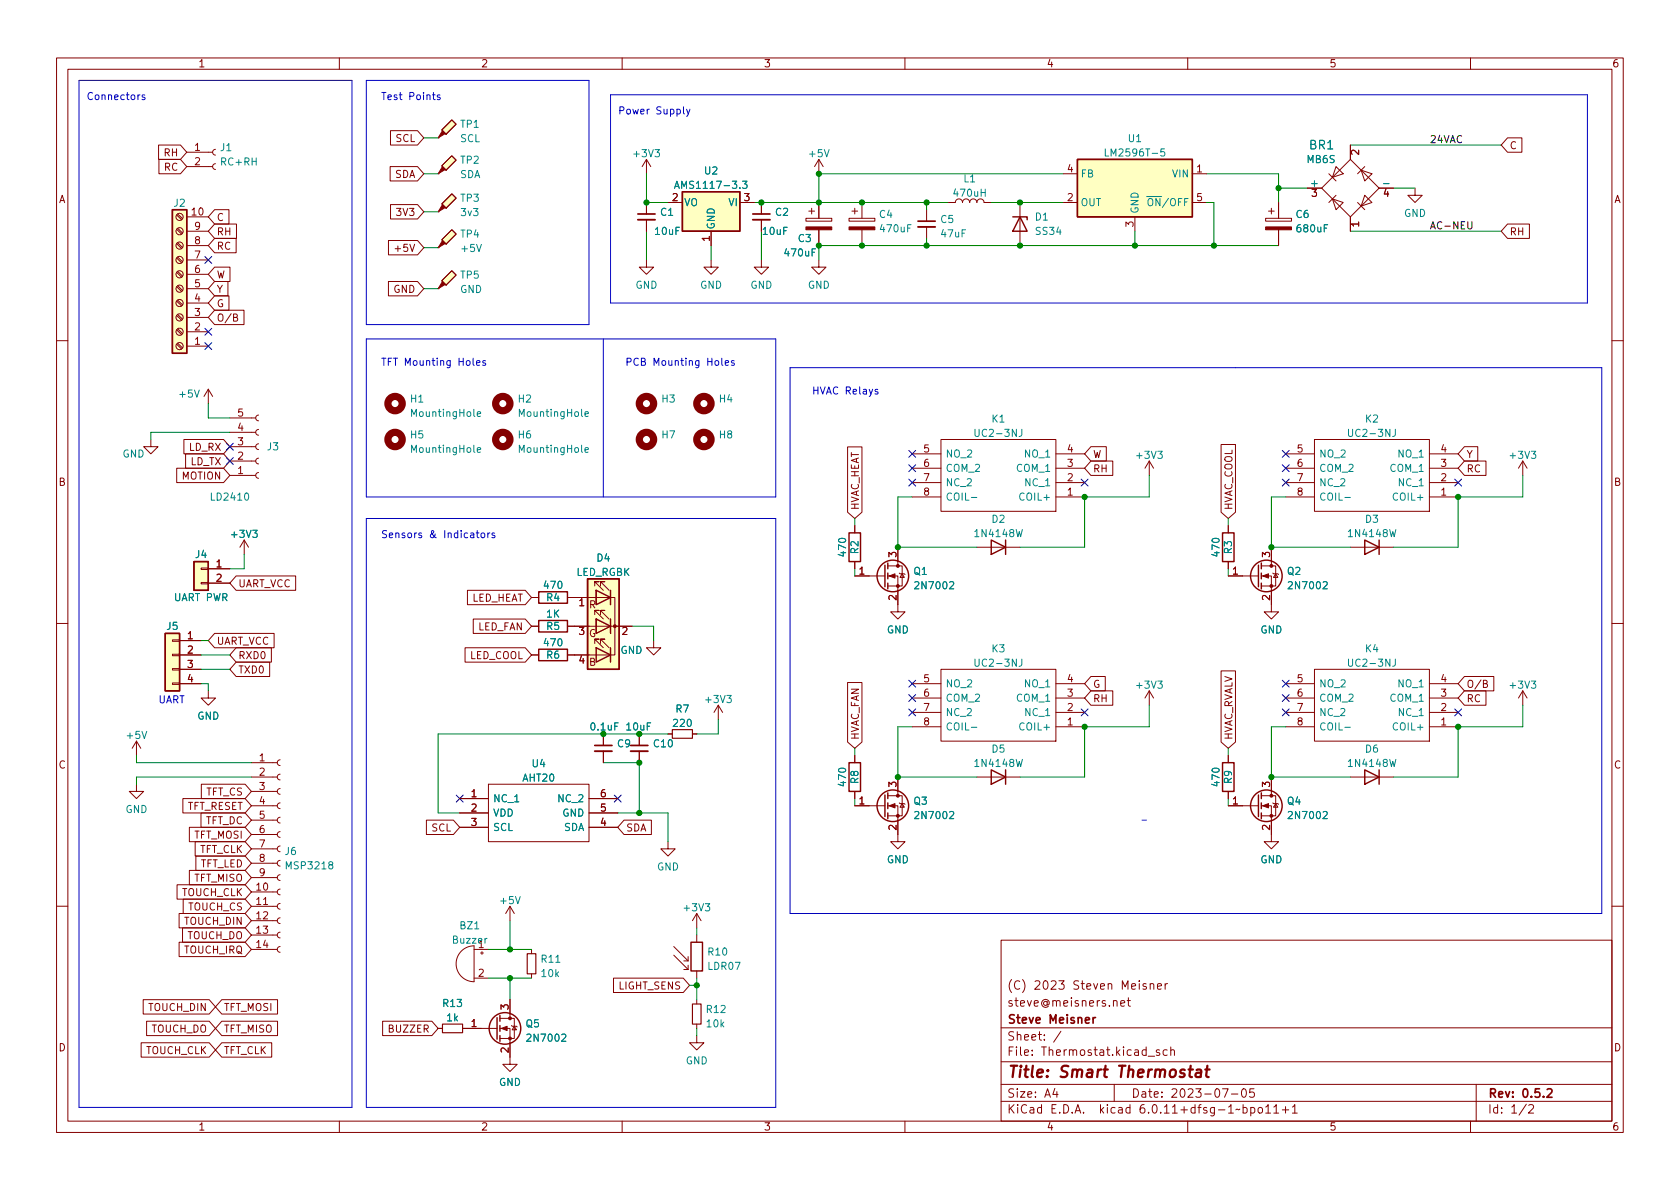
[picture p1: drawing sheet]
<svg xmlns="http://www.w3.org/2000/svg" width="297mm" height="210mm" viewBox="0 0 297 210" stroke-linecap="round" stroke-linejoin="round" font-family="sans-serif">
<defs><g id="words">
<g font-size="2.8" fill="#840000">
<text x="178" y="191.2">Title:</text>
<text x="187.3" y="191.2">Smart</text>
<text x="197.9" y="191.2">Thermostat</text>
</g>
<text font-size="2.1" fill="#008484" x="231.4" y="26.9">BR1</text>
<g font-size="2.1" fill="#840000">
<text x="178" y="178.5">steve@meisners.net</text>
<text x="178" y="175.5">(C)</text>
<text x="182.8" y="175.5">2023</text>
<text x="189.8" y="175.5">Steven</text>
<text x="198.5" y="175.5">Meisner</text>
<text x="178" y="184.5">Sheet:</text>
<text x="178" y="181.5">Steve</text>
<text x="185.4" y="181.5">Meisner</text>
<text x="178" y="187.2">File:</text>
<text x="184.4" y="187.2">Thermostat.kicad_sch</text>
<text x="178" y="197.4">KiCad</text>
<text x="178" y="194.6">Size:</text>
<text x="184.7" y="194.6">A4</text>
<text x="185.7" y="197.4">E.D.A.</text>
<text x="194.6" y="197.4">kicad</text>
<text x="200" y="194.6">Date:</text>
<text x="201.8" y="197.4">6.0.11+dfsg-1~bpo11+1</text>
<text x="207" y="194.6">2023-07-05</text>
<text x="263" y="194.6">Rev:</text>
<text x="263" y="197.4">Id:</text>
<text x="267.1" y="197.4">1/2</text>
<text x="269.1" y="194.6">0.5.2</text>
</g>
<g font-size="1.8" fill="#0000c2">
<text x="15.2" y="17.7">Connectors</text>
<text x="67.3" y="17.7">Test</text>
<text x="72.2" y="17.7">Points</text>
<text x="109.2" y="20.2">Power</text>
<text x="116" y="20.2">Supply</text>
<text x="67.3" y="64.7">TFT Mounting</text>
<text x="81.1" y="64.7">Holes</text>
<text x="110.5" y="64.7">PCB</text>
<text x="115.4" y="64.7">Mounting</text>
<text x="125.1" y="64.7">Holes</text>
<text x="143.5" y="69.7">HVAC Relays</text>
<text x="67.3" y="95.1">Sensors</text>
<text x="75.9" y="95.1">&amp;</text>
<text x="78.6" y="95.1">Indicators</text>
<text x="27.9" y="124.4">UART</text>
</g>
<g font-size="1.8" fill="#840000">
<text x="35" y="12.3">1</text>
<text x="85" y="12.3">2</text>
<text x="135" y="12.3">3</text>
<text x="185" y="12.3">4</text>
<text x="235" y="12.3">5</text>
<text x="285" y="12.3">6</text>
<text x="28.8" y="28">RH</text>
<text x="34.2" y="26.7">1</text>
<text x="34.2" y="29.2">2</text>
<text x="69.8" y="25.5">SCL</text>
<text x="266.9" y="26.8">C</text>
<text x="28.9" y="30.6">RC</text>
<text x="69.8" y="31.8">SDA</text>
<text x="118.7" y="35.6">2</text>
<text x="131.4" y="35.6">3</text>
<text x="188.5" y="35.6">2</text>
<text x="188.5" y="30.5">4</text>
<text x="211.4" y="30.5">1</text>
<text x="211.4" y="35.6">5</text>
<text x="244.4" y="35.6">4</text>
<text x="10.4" y="36.3">A</text>
<text x="33.6" y="38.1">10</text>
<text x="34.2" y="40.6">9</text>
<text x="38.3" y="39.5">C</text>
<text x="69.8" y="38.6">3V3</text>
<text x="200.4" y="40.3" transform="rotate(-90 200.4 40.3)">3</text>
<text x="241.1" y="40.3" transform="rotate(-90 241.1 40.3)">1</text>
<text x="285.4" y="36.3">A</text>
<text x="34.2" y="45.7">7</text>
<text x="34.2" y="43.2">8</text>
<text x="38.3" y="42">RH</text>
<text x="38.3" y="44.5">RC</text>
<text x="69.5" y="44.9">+5V</text>
<text x="125.5" y="42.8" transform="rotate(-90 125.5 42.8)">1</text>
<text x="266.9" y="42">RH</text>
<text x="34.2" y="53.3">4</text>
<text x="34.2" y="50.8">5</text>
<text x="34.2" y="48.3">6</text>
<text x="38.3" y="49.6">W</text>
<text x="38.3" y="52.2">Y</text>
<text x="69.5" y="52.2">GND</text>
<text x="34.2" y="58.4">2</text>
<text x="34.2" y="55.9">3</text>
<text x="38.3" y="54.7">G</text>
<text x="38.3" y="57.2">O/B</text>
<text x="34.2" y="61">1</text>
<text x="41.9" y="76.2">4</text>
<text x="41.9" y="73.7">5</text>
<text x="33.3" y="80.1">LD_RX</text>
<text x="33.6" y="82.6">LD_TX</text>
<text x="41.9" y="83.8">1</text>
<text x="41.9" y="81.3">2</text>
<text x="41.9" y="78.7">3</text>
<text x="163.1" y="80">5</text>
<text x="163.1" y="82.5">6</text>
<text x="188.5" y="82.5">3</text>
<text x="188.5" y="80">4</text>
<text x="193.2" y="81.4">W</text>
<text x="193.2" y="83.9">RH</text>
<text x="229.2" y="80">5</text>
<text x="229.2" y="82.5">6</text>
<text x="254.6" y="82.5">3</text>
<text x="254.6" y="80">4</text>
<text x="259.2" y="81.4">Y</text>
<text x="259.2" y="83.9">RC</text>
<text x="10.3" y="86.3">B</text>
<text x="32" y="85.2">MOTION</text>
<text x="163.1" y="85.1">7</text>
<text x="163.1" y="87.6">8</text>
<text x="188.5" y="87.6">1</text>
<text x="188.5" y="85.1">2</text>
<text x="229.2" y="85.1">7</text>
<text x="229.2" y="87.6">8</text>
<text x="254.6" y="87.6">1</text>
<text x="254.6" y="85.1">2</text>
<text x="285.3" y="86.3">B</text>
<text x="152.2" y="90.3" transform="rotate(-90 152.2 90.3)">HVAC_HEAT</text>
<text x="218.3" y="90.3" transform="rotate(-90 218.3 90.3)">HVAC_COOL</text>
<text x="38.1" y="100.3">1</text>
<text x="151.7" y="101.6">1</text>
<text x="158.5" y="98.7" transform="rotate(-90 158.5 98.7)">3</text>
<text x="217.8" y="101.6">1</text>
<text x="224.5" y="98.7" transform="rotate(-90 224.5 98.7)">3</text>
<text x="38.1" y="102.9">2</text>
<text x="42.1" y="104.2">UART_VCC</text>
<text x="83.4" y="106.8">LED_HEAT</text>
<text x="102.2" y="108">1</text>
<text x="104.1" y="108">R</text>
<text x="158.5" y="106.3" transform="rotate(-90 158.5 106.3)">2</text>
<text x="224.5" y="106.3" transform="rotate(-90 224.5 106.3)">2</text>
<text x="33" y="113">1</text>
<text x="84.5" y="111.9">LED_FAN</text>
<text x="104.1" y="113">G</text>
<text x="33" y="115.6">2</text>
<text x="33" y="118.1">3</text>
<text x="38.3" y="114.4">UART_VCC</text>
<text x="42.1" y="119.5">TXD0</text>
<text x="42.1" y="116.9">RXD0</text>
<text x="83" y="116.9">LED_COOL</text>
<text x="102.2" y="118.1">4</text>
<text x="104.1" y="118.1">B</text>
<text x="33" y="120.6">4</text>
<text x="163.1" y="120.6">5</text>
<text x="163.1" y="123.2">6</text>
<text x="163.1" y="125.7">7</text>
<text x="188.5" y="125.7">2</text>
<text x="188.5" y="123.2">3</text>
<text x="188.5" y="120.6">4</text>
<text x="193.2" y="124.6">RH</text>
<text x="193.2" y="122">G</text>
<text x="229.2" y="120.6">5</text>
<text x="229.2" y="123.2">6</text>
<text x="229.2" y="125.7">7</text>
<text x="254.6" y="125.7">2</text>
<text x="254.6" y="123.2">3</text>
<text x="254.6" y="120.6">4</text>
<text x="259.2" y="122">O/B</text>
<text x="259.2" y="124.6">RC</text>
<text x="152.2" y="130.9" transform="rotate(-90 152.2 130.9)">HVAC_FAN</text>
<text x="163.1" y="128.3">8</text>
<text x="188.5" y="128.3">1</text>
<text x="218.3" y="130.9" transform="rotate(-90 218.3 130.9)">HVAC_RVALV</text>
<text x="229.2" y="128.3">8</text>
<text x="254.6" y="128.3">1</text>
<text x="10.3" y="136.3">C</text>
<text x="45.7" y="134.6">1</text>
<text x="45.7" y="137.2">2</text>
<text x="285.3" y="136.3">C</text>
<text x="33.1" y="143.6">TFT_RESET</text>
<text x="36.4" y="141.1">TFT_CS</text>
<text x="45.7" y="139.7">3</text>
<text x="45.7" y="142.2">4</text>
<text x="83.1" y="141">1</text>
<text x="83.1" y="143.5">2</text>
<text x="106" y="143.5">5</text>
<text x="106" y="141">6</text>
<text x="151.7" y="142.2">1</text>
<text x="158.5" y="139.4" transform="rotate(-90 158.5 139.4)">3</text>
<text x="217.8" y="142.2">1</text>
<text x="224.5" y="139.4" transform="rotate(-90 224.5 139.4)">3</text>
<text x="34.3" y="148.7">TFT_MOSI</text>
<text x="36.3" y="146.1">TFT_DC</text>
<text x="45.7" y="144.8">5</text>
<text x="45.7" y="147.3">6</text>
<text x="45.7" y="149.9">7</text>
<text x="76.2" y="147.4">SCL</text>
<text x="83.1" y="146">3</text>
<text x="106" y="146">4</text>
<text x="110.6" y="147.4">SDA</text>
<text x="158.5" y="147" transform="rotate(-90 158.5 147)">2</text>
<text x="224.5" y="147" transform="rotate(-90 224.5 147)">2</text>
<text x="35.3" y="151.2">TFT_CLK</text>
<text x="35.4" y="153.8">TFT_LED</text>
<text x="45.7" y="152.4">8</text>
<text x="45.7" y="154.9">9</text>
<text x="32.1" y="158.8">TOUCH_CLK</text>
<text x="33.2" y="161.4">TOUCH_CS</text>
<text x="34.3" y="156.3">TFT_MISO</text>
<text x="45.1" y="157.5">10</text>
<text x="45.1" y="160">11</text>
<text x="32.5" y="163.9">TOUCH_DIN</text>
<text x="33.1" y="166.5">TOUCH_DO</text>
<text x="45.1" y="162.6">12</text>
<text x="45.1" y="165.1">13</text>
<text x="45.1" y="167.6">14</text>
<text x="32.5" y="169">TOUCH_IRQ</text>
<text x="84.4" y="172.7">2</text>
<text x="26.1" y="179.2">TOUCH_DIN</text>
<text x="39.5" y="179.2">TFT_MOSI</text>
<text x="89.9" y="178.7" transform="rotate(-90 89.9 178.7)">3</text>
<text x="109.3" y="175.4">LIGHT_SENS</text>
<text x="26.7" y="183">TOUCH_DO</text>
<text x="39.5" y="183">TFT_MISO</text>
<text x="68.5" y="183">BUZZER</text>
<text x="83.1" y="181.6">1</text>
<text x="10.3" y="186.3">D</text>
<text x="25.8" y="186.8">TOUCH_CLK</text>
<text x="39.5" y="186.8">TFT_CLK</text>
<text x="89.9" y="186.3" transform="rotate(-90 89.9 186.3)">2</text>
<text x="285.3" y="186.3">D</text>
<text x="35" y="200.3">1</text>
<text x="85" y="200.3">2</text>
<text x="135" y="200.3">3</text>
<text x="185" y="200.3">4</text>
<text x="235" y="200.3">5</text>
<text x="285" y="200.3">6</text>
</g>
<g font-size="1.8" fill="#008484">
<text x="81.3" y="23">TP1</text>
<text x="38.8" y="27.1">J1</text>
<text x="38.8" y="29.6">RC+RH</text>
<text x="81.3" y="29.3">TP2</text>
<text x="81.3" y="25.5">SCL</text>
<text x="111.7" y="28.2">+3V3</text>
<text x="142.8" y="28.2">+5V</text>
<text x="195.1" y="28">LM2596T-5</text>
<text x="199.3" y="25.5">U1</text>
<text x="230.9" y="29.2">MB6S</text>
<text x="81.3" y="31.9">SDA</text>
<text x="119.1" y="33.8">AMS1117-3.3</text>
<text x="124.4" y="31.2">U2</text>
<text x="168.3" y="35.2">470uH</text>
<text x="170.3" y="32.6">L1</text>
<text x="191" y="31.8">FB</text>
<text x="207.1" y="31.8">VIN</text>
<text x="231.5" y="33">+</text>
<text x="30.6" y="36.9">J2</text>
<text x="81.3" y="36.1">TP3</text>
<text x="81.3" y="38.6">3v3</text>
<text x="115.6" y="41.9">10uF</text>
<text x="116.6" y="38.5">C1</text>
<text x="120.9" y="36.8">VO</text>
<text x="126.8" y="40.6" transform="rotate(-90 126.8 40.6)">GND</text>
<text x="128.7" y="36.8">VI</text>
<text x="134.6" y="41.9">10uF</text>
<text x="136.9" y="38.5">C2</text>
<text x="155.3" y="38.9">C4</text>
<text x="155.3" y="41.5">470uF</text>
<text x="166.2" y="39.8">C5</text>
<text x="182.9" y="39.4">D1</text>
<text x="182.9" y="41.9">SS34</text>
<text x="191" y="36.8">OUT</text>
<text x="201.7" y="37.8" transform="rotate(-90 201.7 37.8)">GND</text>
<text x="202.7" y="36.8">~{ON}/OFF</text>
<text x="229" y="38.9">C6</text>
<text x="229" y="41.5">680uF</text>
<text x="248.2" y="38.7">GND</text>
<text x="81.3" y="42.4">TP4</text>
<text x="81.3" y="44.9">+5V</text>
<text x="138.4" y="45.7">470uF</text>
<text x="141" y="43.2">C3</text>
<text x="166.2" y="42.3">47uF</text>
<text x="81.3" y="49.6">TP5</text>
<text x="81.3" y="52.2">GND</text>
<text x="112.3" y="51.4">GND</text>
<text x="123.7" y="51.4">GND</text>
<text x="132.6" y="51.4">GND</text>
<text x="142.8" y="51.4">GND</text>
<text x="31.4" y="70.7">+5V</text>
<text x="72.4" y="71.6">H1</text>
<text x="91.4" y="71.6">H2</text>
<text x="116.8" y="71.6">H3</text>
<text x="127" y="71.6">H4</text>
<text x="72.4" y="77.9">H5</text>
<text x="72.4" y="74.1">MountingHole</text>
<text x="91.4" y="77.9">H6</text>
<text x="91.4" y="74.1">MountingHole</text>
<text x="116.8" y="77.9">H7</text>
<text x="127" y="77.9">H8</text>
<text x="172" y="77.6">UC2-3NJ</text>
<text x="175.2" y="75.1">K1</text>
<text x="238" y="77.6">UC2-3NJ</text>
<text x="241.3" y="75.1">K2</text>
<text x="21.6" y="81.3">GND</text>
<text x="47.1" y="80">J3</text>
<text x="72.4" y="80.4">MountingHole</text>
<text x="91.4" y="80.4">MountingHole</text>
<text x="167.1" y="81.3">NO_2</text>
<text x="167.1" y="83.8">COM_2</text>
<text x="179.5" y="83.8">COM_1</text>
<text x="180.9" y="81.3">NO_1</text>
<text x="200.6" y="81.5">+3V3</text>
<text x="233.2" y="81.3">NO_2</text>
<text x="233.2" y="83.8">COM_2</text>
<text x="245.6" y="83.8">COM_1</text>
<text x="247" y="81.3">NO_1</text>
<text x="266.6" y="81.5">+3V3</text>
<text x="37" y="88.9">LD2410</text>
<text x="167.1" y="86.4">NC_2</text>
<text x="167.1" y="88.9">COIL-</text>
<text x="180" y="88.9">COIL+</text>
<text x="181" y="86.4">NC_1</text>
<text x="233.2" y="86.4">NC_2</text>
<text x="233.2" y="88.9">COIL-</text>
<text x="246" y="88.9">COIL+</text>
<text x="247" y="86.4">NC_1</text>
<text x="40.6" y="95.5">+3V3</text>
<text x="172" y="95.4">1N4148W</text>
<text x="175.2" y="92.8">D2</text>
<text x="238.1" y="95.4">1N4148W</text>
<text x="241.3" y="92.8">D3</text>
<text x="34.4" y="99.1">J4</text>
<text x="105.4" y="99.7">D4</text>
<text x="150" y="98.7" transform="rotate(-90 150 98.7)">470</text>
<text x="152.2" y="98.1" transform="rotate(-90 152.2 98.1)">R2</text>
<text x="216" y="98.7" transform="rotate(-90 216 98.7)">470</text>
<text x="218.2" y="98.1" transform="rotate(-90 218.2 98.1)">R3</text>
<text x="30.7" y="106.7">UART PWR</text>
<text x="95.9" y="104.5">470</text>
<text x="96.5" y="106.7">R4</text>
<text x="101.9" y="102.2">LED_RGBK</text>
<text x="161.4" y="102">Q1</text>
<text x="161.4" y="104.6">2N7002</text>
<text x="227.5" y="102">Q2</text>
<text x="227.5" y="104.6">2N7002</text>
<text x="29.3" y="111.8">J5</text>
<text x="96.5" y="111.8">R5</text>
<text x="96.5" y="109.6">1K</text>
<text x="156.7" y="112.4">GND</text>
<text x="222.8" y="112.4">GND</text>
<text x="95.9" y="114.7">470</text>
<text x="96.5" y="116.8">R6</text>
<text x="109.6" y="116">GND</text>
<text x="172" y="118.3">UC2-3NJ</text>
<text x="175.2" y="115.7">K3</text>
<text x="238" y="118.3">UC2-3NJ</text>
<text x="241.3" y="115.7">K4</text>
<text x="124.4" y="124.7">+3V3</text>
<text x="167.1" y="121.9">NO_2</text>
<text x="167.1" y="124.5">COM_2</text>
<text x="179.5" y="124.5">COM_1</text>
<text x="180.9" y="121.9">NO_1</text>
<text x="200.6" y="122.2">+3V3</text>
<text x="233.2" y="121.9">NO_2</text>
<text x="233.2" y="124.5">COM_2</text>
<text x="245.6" y="124.5">COM_1</text>
<text x="247" y="121.9">NO_1</text>
<text x="266.6" y="122.2">+3V3</text>
<text x="22.1" y="131">+5V</text>
<text x="34.8" y="127.6">GND</text>
<text x="104.1" y="129.5">0.1uF</text>
<text x="110.5" y="129.5">10uF</text>
<text x="118.8" y="128.9">220</text>
<text x="119.3" y="126.4">R7</text>
<text x="167.1" y="127">NC_2</text>
<text x="167.1" y="129.5">COIL-</text>
<text x="180" y="129.5">COIL+</text>
<text x="181" y="127">NC_1</text>
<text x="233.2" y="127">NC_2</text>
<text x="233.2" y="129.5">COIL-</text>
<text x="246" y="129.5">COIL+</text>
<text x="247" y="127">NC_1</text>
<text x="93.9" y="136.1">U4</text>
<text x="109" y="132.5">C9</text>
<text x="115.4" y="132.5">C10</text>
<text x="172" y="136">1N4148W</text>
<text x="175.2" y="133.5">D5</text>
<text x="238.1" y="136">1N4148W</text>
<text x="241.3" y="133.5">D6</text>
<text x="87.1" y="142.2">NC_1</text>
<text x="92.3" y="138.6">AHT20</text>
<text x="98.4" y="142.2">NC_2</text>
<text x="150" y="139.3" transform="rotate(-90 150 139.3)">470</text>
<text x="152.2" y="138.7" transform="rotate(-90 152.2 138.7)">R8</text>
<text x="161.4" y="142.7">Q3</text>
<text x="216" y="139.3" transform="rotate(-90 216 139.3)">470</text>
<text x="218.2" y="138.7" transform="rotate(-90 218.2 138.7)">R9</text>
<text x="227.5" y="142.7">Q4</text>
<text x="22.1" y="144.1">GND</text>
<text x="87.1" y="144.8">VDD</text>
<text x="87.1" y="147.3">SCL</text>
<text x="99.4" y="144.8">GND</text>
<text x="99.7" y="147.3">SDA</text>
<text x="161.4" y="145.2">2N7002</text>
<text x="227.5" y="145.2">2N7002</text>
<text x="50.2" y="151.6">J6</text>
<text x="50.2" y="154.1">MSP3218</text>
<text x="116.1" y="154.3">GND</text>
<text x="156.7" y="153">GND</text>
<text x="222.8" y="153">GND</text>
<text x="88.2" y="160.3">+5V</text>
<text x="120.6" y="161.5">+3V3</text>
<text x="79.8" y="167.2">Buzzer</text>
<text x="81.1" y="164.7">BZ1</text>
<text x="84.4" y="167.6">1</text>
<text x="95.5" y="170.6">R11</text>
<text x="95.5" y="173.2">10k</text>
<text x="125" y="169.3">R10</text>
<text x="125" y="171.9">LDR07</text>
<text x="78.1" y="178.4">R13</text>
<text x="124.7" y="179.5">R12</text>
<text x="78.8" y="181">1k</text>
<text x="92.8" y="182">Q5</text>
<text x="92.8" y="184.6">2N7002</text>
<text x="124.7" y="182">10k</text>
<text x="121.2" y="188.6">GND</text>
<text x="88.2" y="192.4">GND</text>
</g>
<g font-size="1.8">
<text x="252.7" y="25.3">24VAC</text>
<text x="252.7" y="40.5">AC-NEU</text>
</g>
</g></defs>
<g fill="none" stroke="#840000" stroke-width=".18">
<path d="M10 10.2h277v190.1h-277zM12 12.2h273v186.1h-273zM60 10.2v2M110 10.2v2M160 10.2v2M210 10.2v2M260 10.2v2M28 25.6h3.9l1.1 1.3-1.1 1.3h-3.9zM28.1 28.2h3.8l1.1 1.3-1.1 1.2h-3.8zM31.2 38l.9 .9M31.4 37.8l.9 .9M33 38.3h3.8"/>
<path d="M33 29.5h4.6M33 26.9h4.6M37.9 37.1h2.6v2.5h-2.6l-1.1-1.3zM37.9 39.6h3.9v2.6h-3.9l-1.1-1.3zM38.1 29l-.4 .1-.1 .4 .1 .3 .4 .2M38.1 26.4l-.4 .2-.1 .3 .1 .4 .4 .1M69 29.5h4.8l1.1 1.2-1.1 1.3h-4.8zM69 23.1h4.8l1.1 1.3-1.1 1.2h-4.8zM69 36.2h4.8l1.1 1.3-1.1 1.2h-4.8zM77.5 30.7h.1M77.5 24.4h.1M77.5 37.5h.1"/>
<path d="M78.1 29.3l1.8-1.7 .7 .7-1.7 1.8zM78.1 23l1.8-1.8 .7 .8-1.7 1.7zM78.1 36.1l1.8-1.8 .8 .7-1.8 1.8zM114.3 28.2v2.5M114.3 35.8v2M114.3 38.9v2M114.3 28.2l-.8 1.3M114.3 28.2l.8 1.3M118.1 35.8h2.5M130.8 35.8h2.5M134.6 35.8v2M134.6 38.9v2"/>
<path d="M142.5 38.6h4.6v.5h-4.6zM143 37.3h1M143.5 36.8v1M144.8 28.2v2.5M144.8 35.8v2.8M144.8 28.2l-.8 1.3M144.8 28.2l.7 1.3M150.1 38.6h4.6v.5h-4.6zM150.6 37.3h1M151.1 36.8v1M152.4 35.8v2.8M163.8 37.1v2"/>
<path d="M167.6 35.8h1.3M174 35.8h1.3M180.3 35.8v7.6M188 35.8h2.5M188 30.7h2.5M200.7 38.3v2.6M210.8 35.8h2.6M210.8 30.7h2.6M223.8 38.6h4.5v.5h-4.5zM224.3 37.3h1M224.8 36.8v1M226.1 35.8v2.8"/>
<path d="M231.1 33.3h2.6M232 33.5h.8l-.5 .4 .4 .2v.5l-.2 .1-.5-.1M234.9 30.7l1.3 1.3M235.6 35.2l1.9 .6-1.3 1.3zM236.2 29.5l1.3 1.2-1.9 .7zM236.2 34.5l-1.3 1.3M238.8 28.2l5 5.1-5 5-5.1-5zM238.8 25.6v2.6M238.8 38.3v2.6M240 35.8l1.3 1.3M240.2 39.6h-1.2l.3 .4M240.2 26.6v.7l-.9-.7-.3 .2 .1 .5"/>
<path d="M240.7 30.1l1.9 .6-1.3 1.3zM241.3 34.5l1.3 1.3-1.9 .6zM241.3 29.5l-1.3 1.2M243.8 33.3h2.6M245 33.4l-.3 .9h.8M250.2 33.3v1.2h1.3l-1.3 1.3-1.3-1.3h1.3M266.5 39.6h3.9v2.6h-3.9l-1.1-1.3zM266.5 24.4h2.6v2.5h-2.6l-1.1-1.3zM31.2 40.6l.9 .8M31.2 43.1l.9 .8M31.2 45.6l.9 .9M31.2 48.2l.9 .8"/>
<path d="M31.2 50.7l.9 .9M31.2 53.3l.9 .8M31.2 55.8l.9 .8M31.2 58.3l.9 .9M31.4 40.4l.9 .8M31.4 42.9l.9 .9M31.4 45.5l.9 .8M31.4 48l.9 .8M31.4 50.5l.9 .9M31.4 53.1l.9 .8M31.4 55.6l.9 .9M31.4 58.2l.9 .8"/>
<path d="M33 58.7h3.8M33 56.1h3.8M33 53.6h3.8M33 51h3.8M33 48.5h3.8M33 46h3.8M33 43.4h3.8M33 40.9h3.8M37.9 52.3h2.6v2.6h-2.6l-1.1-1.3zM37.9 47.2h2.8v2.6h-2.8l-1.1-1.3zM37.9 54.9h5.2v2.5h-5.2l-1.1-1.3zM37.9 49.8h2.4v2.5h-2.4l-1.1-1.3z"/>
<path d="M37.9 42.2h3.9v2.5h-3.9l-1.1-1.3zM41.3 56.1h.5l.2-.2-.1-.3-.6-.1v1.3h.5l.2-.1v-.3l-.3-.3M68.7 49.8h5.1l1.1 1.2-1.1 1.3h-5.1zM68.7 42.5h5.1l1.1 1.3-1.1 1.3h-5.1zM72.5 43.2l.4 1.3 .4-1.3M77.5 51h.1M77.5 43.8h.1M78.1 49.7l1.8-1.8 .7 .7-1.7 1.8zM78.1 42.4l1.8-1.8 .8 .8-1.8 1.8zM114.3 46v1.2h1.3l-1.3 1.3-1.3-1.3h1.3M125.7 46v1.2h1.3l-1.3 1.3-1.2-1.3h1.2M125.7 40.9v2.5"/>
<path d="M134.6 46v1.2h1.3l-1.3 1.3-1.3-1.3h1.3M144.8 46v1.2h1.2l-1.2 1.3-1.3-1.3h1.3M144.8 40.6v2.8M152.4 40.6v2.8M163.8 40.1v2.1M226.1 40.6v2.8M10 60.2h2M26.7 77.7v1.3h1.2l-1.2 1.3-1.3-1.3h1.3M31.2 60.9l.9 .8M31.4 60.7l.9 .8M32.5 77.7h7l1.1 1.3-1.1 1.3h-7zM33 61.2h3.8"/>
<path d="M36.8 68.8l-.7 1.3M36.8 68.8v2.6M36.8 68.8l.8 1.3M40.6 73.9h4.6M40.6 76.4h4.6M40.6 79h4.6M45.7 73.4l-.3 .1-.2 .4 .2 .4 .3 .1M45.7 75.9l-.3 .2-.2 .3 .2 .4 .3 .2M45.7 78.5l-.3 .1-.2 .4 .2 .3 .3 .2M149.9 79h2.5v11.6l-1.3 1.1-1.2-1.1zM166.4 77.7h20.3v12.7h-20.3zM192.9 79h2.7v2.5h-2.7l-1.1-1.2z"/>
<path d="M215.9 78.6h2.5v12l-1.2 1.1-1.3-1.1zM232.4 77.7h20.3v12.7h-20.3zM258.9 79h2.4v2.5h-2.4l-1.1-1.2zM285 60.2h2M31.2 82.8h8.3l1.1 1.3-1.1 1.2h-8.3zM32.8 80.3h6.7l1.1 1.2-1.1 1.3h-6.7zM40.6 81.5h4.6M40.6 84.1h4.6M43.2 95.5l-.8 1.3M43.2 95.5v2.5M43.2 95.5l.7 1.3M45.7 81l-.3 .2-.2 .3 .2 .4 .3 .1"/>
<path d="M45.7 83.6l-.3 .1-.2 .4 .2 .3 .3 .2M151.1 93v1.2M151.1 99.3v1.3M158.7 96.8v3.3M161.3 87.9h5.1M161.3 85.3h5.1M161.3 82.8h5.1M161.3 80.3h5.1M172.7 96.8h7.6M186.7 87.9h5.1M186.7 85.3h5.1M186.7 82.8h5.1"/>
<path d="M186.7 80.3h5.1M192.9 81.5h3.9v2.6h-3.9l-1.1-1.3zM203.2 81.5l-.8 1.3M203.2 81.5v2.6M203.2 81.5l.8 1.3M217.2 93v1.2M217.2 99.3v1.3M224.8 96.8v3.3M227.3 87.9h5.1M227.3 85.3h5.1M227.3 82.8h5.1M227.3 80.3h5.1"/>
<path d="M238.8 96.8h7.6M252.7 87.9h5.1M252.7 85.3h5.1M252.7 82.8h5.1M252.7 80.3h5.1M258.9 81.5h3.8v2.6h-3.8l-1.1-1.3zM269.2 81.5l-.7 1.3M269.2 81.5v2.6M269.2 81.5l.8 1.3M10 110.2h2M30.5 118.2h1.2v.3h-1.2zM30.5 115.7h1.2v.2h-1.2z"/>
<path d="M30.5 113.2h1.2v.2h-1.2zM31.7 115.8h3.9M31.7 113.3h3.9M31.7 118.4h3.9M35.6 103h1.2v.2h-1.2zM35.6 100.5h1.2v.2h-1.2zM36.8 100.6h3.8M36.8 103.1h3.8M37.9 112h10.6v2.5h-10.6l-1.1-1.2zM41.8 101.8h10.5v2.6h-10.5l-1.2-1.3zM41.8 117.1h5.9v2.5h-5.9l-1.2-1.2zM41.8 114.5h6.2v2.6h-6.2l-1.2-1.3z"/>
<path d="M82.2 114.5h10.7l1.1 1.3-1.1 1.3h-10.7zM82.6 104.4h10.3l1.1 1.3-1.1 1.2h-10.3zM83.7 109.5h9.2l1.1 1.2-1.1 1.3h-9.2zM94 105.7h1.2M94 110.7h1.2M94 115.8h1.2M100.3 105.7h8.4v10.1h-1M100.3 110.7h11.5M100.3 115.8h7.6M102.4 110.9h.8l-.4 .5 .4 .1v.6l-.2 .1-.6-.1M102.5 106.2l.4-.3v1.2M102.8 116l-.3 .9h.8"/>
<path d="M105.2 113.8v-.8h.7h-.7l1.5 1.5M105.2 108.7v-.8h.7h-.7l1.5 1.6M105.2 103.6v-.7h.7h-.7l1.5 1.5M105.4 109.5v2.5zM105.4 109.5h.1M105.4 104.4v2.5zM105.4 104.4h.1M106.2 113.8v-.8h.7h-.7l1.5 1.5M106.2 108.7v-.8h.7h-.7l1.5 1.6M106.2 103.6v-.7h.7h-.7l1.5 1.5M107.9 109.5v2.5M107.9 104.4v2.5"/>
<path d="M110.1 111.1l.5-.2 .3 .4-.8 .9h.8M115.6 113.3v1.2h-1.3l1.3 1.3 1.2-1.3h-1.2M151.1 101.8h5.4M157 101.8h1.7v6.4h1.3l-1.3 1.3-1.2-1.3h1.2M157 100.1h2.5v3.5h-2.5M159 101.3l.1 .2h.8l.1 .1M159.5 101.5l.4 .6h-.8zM166.4 118.4h20.3v12.7h-20.3zM192.9 119.6h2.5v2.6h-2.5l-1.1-1.3zM215.9 118.6h2.5v12.6l-1.2 1.1-1.3-1.1zM217.2 101.8h5.3M223 101.8h1.8v6.4h1.3l-1.3 1.3-1.3-1.3h1.3"/>
<path d="M223 100.1h2.6v3.5h-2.6M225 101.3l.2 .2h.7l.2 .1M225.6 101.5l.3 .6h-.7zM232.4 118.4h20.3v12.7h-20.3zM258.9 119.6h5.2v2.6h-5.2l-1.1-1.3zM285 110.2h2M24.1 138.7v1.2h1.3l-1.3 1.3-1.2-1.3h1.2M24.1 131.1l-.7 1.2M24.1 131.1v2.5M24.1 131.1l.8 1.2M30.5 120.8h1.2v.2h-1.2zM31.7 120.9h3.9"/>
<path d="M35.6 138.7h7.7l1.1 1.2-1.1 1.3h-7.7zM36.8 122.2v1.2h1.3l-1.3 1.3-1.2-1.3h1.2M44.4 139.9h4.6M44.4 137.4h4.6M44.4 134.9h4.6M49.5 139.4l-.3 .2-.2 .3 .2 .4 .3 .2M49.5 136.9l-.3 .1-.2 .4 .2 .4 .3 .1M49.5 134.4l-.3 .1-.2 .4 .2 .3 .3 .2M86.4 138.7h17.7v10.1h-17.7zM106.7 129.8v2M106.7 132.8v2.1M113 129.8v2"/>
<path d="M113 132.8v2.1M118.1 129.8h.8M122.4 129.8h.8M127 124.7l-.8 1.3M127 124.7v2.5M127 124.7l.8 1.3M149.9 120.7h2.5v10.5l-1.3 1.1-1.2-1.1zM151.1 133.6v1.3M151.1 139.9v1.3M158.7 137.4v3.3M161.3 128.5h5.1M161.3 126h5.1"/>
<path d="M161.3 123.4h5.1M161.3 120.9h5.1M172.7 137.4h7.6M186.7 128.5h5.1M186.7 126h5.1M186.7 123.4h5.1M186.7 120.9h5.1M192.9 122.2h3.9v2.5h-3.9l-1.1-1.3zM203.2 122.2v2.5M203.2 122.2l-.8 1.2M203.2 122.2l.8 1.2M217.2 133.6v1.3"/>
<path d="M217.2 139.9v1.3M224.8 137.4v3.3M227.3 128.5h5.1M227.3 126h5.1M227.3 123.4h5.1M227.3 120.9h5.1M238.8 137.4h7.6M252.7 128.5h5.1M252.7 126h5.1M252.7 123.4h5.1M252.7 120.9h5.1M258.9 122.2h3.8v2.5h-3.8l-1.1-1.3z"/>
<path d="M262.3 120.9l.5-.1 .1-.1v-.3l-.6-.1v1.3h.5l.1-.2 .1-.3-.3-.2M269.2 122.2v2.5M269.2 122.2l-.7 1.2M269.2 122.2l.8 1.2M31.3 156.5h12l1.1 1.2-1.1 1.3h-12zM32.3 141.2h11l1.1 1.3-1.1 1.3h-11zM32.4 159h10.9l1.1 1.3-1.1 1.2h-10.9zM33.5 153.9h9.8l1.1 1.3-1.1 1.3h-9.8zM33.5 146.3h9.8l1.1 1.3-1.1 1.2h-9.8zM34.5 148.8h8.8l1.1 1.3-1.1 1.3h-8.8zM34.6 151.4h8.7l1.1 1.2-1.1 1.3h-8.7zM35.5 143.8h7.8l1.1 1.2-1.1 1.3h-7.8z"/>
<path d="M44.4 157.7h4.6M44.4 155.2h4.6M44.4 152.6h4.6M44.4 150.1h4.6M44.4 147.6h4.6M44.4 145h4.6M44.4 142.5h4.6M46.6 160h.7M49.5 159.8l-.3 .1-.2 .4 .2 .3 .3 .2M49.5 157.2l-.3 .2-.2 .3 .2 .4 .3 .1M49.5 154.7l-.3 .1-.2 .4 .2 .3 .3 .2M49.5 152.1l-.3 .2-.2 .3 .2 .4 .3 .2"/>
<path d="M49.5 149.6l-.3 .1-.2 .4 .2 .4 .3 .1M49.5 147.1l-.3 .1-.2 .4 .2 .3 .3 .2M49.5 144.5l-.3 .2-.2 .3 .2 .4 .3 .1M49.5 142l-.3 .1-.2 .4 .2 .3 .3 .2M75.4 145h4.8l1.1 1.3-1.1 1.3h-4.8zM81.3 141.2h5.1M81.3 143.8h5.1M81.3 146.3h5.1M104.1 141.2h5.1M104.1 143.8h5.1M104.1 146.3h5.1M110.3 145h4.9v2.6h-4.9l-1.1-1.3z"/>
<path d="M118.1 148.8v1.3h1.3l-1.3 1.3-1.3-1.3h1.3M151.1 142.5h5.4M157 142.5h1.7v6.3h1.3l-1.3 1.3-1.2-1.3h1.2M157 140.7h2.5v3.6h-2.5M159 142l.1 .1h.8l.1 .1M159.5 142.1l.4 .6h-.8zM217.2 142.5h5.3M223 142.5h1.8v6.3h1.3l-1.3 1.3-1.3-1.3h1.3M223 140.7h2.6v3.6h-2.6M225 142l.2 .1h.7l.2 .1M225.6 142.1l.3 .6h-.7zM10 160.2h2"/>
<path d="M25.3 176.8h11.7l1.1 1.2-1.1 1.3h-11.7zM31.7 161.5h11.6l1.1 1.3-1.1 1.3h-11.6zM31.7 166.6h11.6l1.1 1.3-1.1 1.3h-11.6zM32.3 164.1h11l1.1 1.2-1.1 1.3h-11zM39.2 176.8h9.9v2.5h-9.9l-1.1-1.3zM44.4 167.9h4.6M44.4 165.3h4.6M44.4 162.8h4.6M44.4 160.3h4.6M49.5 167.4l-.3 .1-.2 .4 .2 .3 .3 .2M49.5 164.8l-.3 .2-.2 .3 .2 .4 .3 .2M49.5 162.3l-.3 .1-.2 .4 .2 .4 .3 .1"/>
<path d="M81.6 168.2a3.2 3.2 0 0 1 2.2-.9v6.3a3.2 3.2 0 0 1-2.9-2 3.2 3.2 0 0 1 .7-3.4zM83.8 167.9h2.6M83.8 173h2.6M85 168.5h.5M85.2 168.3v.5M90.2 160.3v2.5M90.2 176.8v3.3M90.2 160.3l-.8 1.2M90.2 160.3l.7 1.2M94 167.9v.8M94 172.2v.8M108.5 173h12.3l1.1 1.2-1.1 1.3h-12.3z"/>
<path d="M119.1 168.9l2.6 2.5M119.1 167.4l2.6 2.5M120.9 171.4h.8M120.9 169.9h.8M121.7 169.2v.7M121.7 170.7v.7M123.2 161.5v2.6M123.2 165.3v1.3M123.2 171.7v1.3M123.2 176.8v.7M123.2 161.5l-.8 1.3M123.2 161.5l.8 1.3"/>
<path d="M177 166.3h108v32h-108zM187.2 173.4h.9l-.5 .6 .5 .1v.7l-.2 .1h-.5l-.2-.1M198.1 177.4l.8-.1-.1-.3-.4-.1-.3 .2 .1 .8h.6M199.3 176.9h.6M199.5 176.4v1.3l.4 .2M285 160.2h2M25 184.4h12l1.1 1.3-1.1 1.2h-12zM25.9 180.6h11.1l1.1 1.3-1.1 1.2h-11.1zM39.2 180.6h9.9v2.5h-9.9l-1.1-1.2zM39.2 184.4h8.8v2.5h-8.8l-1.1-1.2zM60 198.3v2M67.6 180.6h8.8l1.1 1.3-1.1 1.2h-8.8z"/>
<path d="M77.5 181.9h.7M81.8 181.9h6.1M88.4 181.9h1.8v6.3h1.2l-1.2 1.3-1.3-1.3h1.3M88.4 180.1h2.5v3.5h-2.5M90.4 181.4l.2 .1h.7l.1 .1M90.9 181.5l.4 .6h-.7zM110 198.3v2M123.2 183.1v1.3h1.3l-1.3 1.3-1.3-1.3h1.3M123.2 181.1v.8M160 198.3v2M177 194.8h108M177 191.8h108"/>
<path d="M177 187.8h108M177 181.8h108M182.5 186.5v.1M182.5 185.7v.1M184.6 183.8v.1M184.6 183v.1M187.6 182.4l-1.3 1.9M197 191.8v3M206.4 185.7l-.5-.1-.3 .3v.4l.2 .3h.6M207 185.8l.2-.2 .4 .1v.9M207 185.1v1.5M210 198.3v2"/>
<path d="M217.7 193.5h1.2M219.7 192.6l.2-.1a.81 .81 0 0 1 .5 .7 .81 .81 0 0 1-.3 .8h-.1a.81 .81 0 0 1-.6-.6 .81 .81 0 0 1 .3-.8zM221.7 192.5h-.7l-.1 .7 .2-.1 .5 .1 .2 .2-.1 .5-.2 .1-.6-.1M223.8 196.8h.8M225.2 195.8l.4-.5v1.5M225.2 196.8h.9M226.7 196.3h1.2M227.3 195.7v1.1M228.5 195.8l.4-.5v1.5M228.5 196.8h.9M260 198.3v2M261 191.8v6.5"/>
<path d="M270.3 195.5l.6-.2 .2 .2 .1 .3-1 1h1"/>
<circle cx="31.7" cy="38.3" r=".63"/>
<circle cx="31.7" cy="58.7" r=".63"/>
<circle cx="31.7" cy="40.9" r=".63"/>
<circle cx="31.7" cy="56.1" r=".63"/>
<circle cx="31.7" cy="46" r=".63"/>
<circle cx="31.7" cy="48.5" r=".63"/>
<circle cx="31.7" cy="43.4" r=".63"/>
<circle cx="31.7" cy="51" r=".63"/>
<circle cx="31.7" cy="53.6" r=".63"/>
<circle cx="31.7" cy="61.2" r=".63"/>
</g>
<path d="M112.8 37.8h3M133.1 37.8h3M162.3 39.1h3.1M105.2 131.8h3M111.5 131.8h3.1M273.6 192.7l.5-.2 .2 .2 .1 .3-.9 1h.9" fill="none" stroke="#840000" stroke-width=".3"/>
<g fill="#ffffc2" stroke="#ffffc2" stroke-width=".18">
<path d="M120.6 33.9h10.2v7h-10.2z"/>
<path d="M78.1 29.3l1.8-1.7 .7 .7-1.7 1.8z"/>
<path d="M190.5 28.2h20.3v10.1h-20.3z"/>
<path d="M78.1 23l1.8-1.8 .7 .8-1.7 1.7z"/>
<path d="M78.1 36.1l1.8-1.8 .8 .7-1.8 1.8z"/>
<path d="M78.1 49.7l1.8-1.8 .7 .7-1.7 1.8z"/>
<path d="M78.1 42.4l1.8-1.8 .8 .8-1.8 1.8z"/>
<path d="M103.9 102.4h5.6v16h-5.6z"/>
<path d="M30.5 37.1h2.5v25.4h-2.5z"/>
<path d="M29.2 112h2.5v10.2h-2.5z"/>
<path d="M34.3 99.3h2.5v5.1h-2.5z"/>
</g>
<g fill="none" stroke="#840000" stroke-width=".25">
<path d="M30.5 37.1h2.5v25.4h-2.5zM120.6 33.9h10.2v7h-10.2zM179.1 38.3h2.5v.6M180.3 38.3l1.3 2.6h-2.5zM190.5 28.2h20.3v10.1h-20.3zM34.3 99.3h2.5v5.1h-2.5zM150.1 94.2h2v5.1h-2zM156.5 99.9v3.9M157 99.6v1M175.3 95.5l2.5 1.3-2.5 1.2zM177.8 95.5v2.5M216.2 94.2h2v5.1h-2z"/>
<path d="M222.5 99.9v3.9M223 99.6v1M241.3 95.5l2.5 1.3-2.5 1.2zM243.8 95.5v2.5M29.2 112h2.5v10.2h-2.5zM95.2 104.6h5.1v2.1h-5.1zM95.2 109.7h5.1v2.1h-5.1zM95.2 114.8h5.1v2h-5.1zM103.9 102.4h5.6v16h-5.6zM105.4 114.5l2.5 1.3-2.5 1.3zM105.4 109.5l2.5 1.2-2.5 1.3zM105.4 104.4l2.5 1.3-2.5 1.2z"/>
<path d="M107.9 104.4v2.5M107.9 109.5v2.5M107.9 114.5v2.6M157 101.3v1.1M157 103.1v1M223 101.3v1.1M223 103.1v1M150.1 134.9h2v5h-2zM175.3 136.1l2.5 1.3-2.5 1.3zM177.8 136.1v2.6M216.2 134.9h2v5h-2zM241.3 136.1l2.5 1.3-2.5 1.3z"/>
<path d="M243.8 136.1v2.6M156.5 140.6v3.8M157 140.2v1M157 142v1M157 143.8v1M222.5 140.6v3.8M223 140.2v1M223 142v1M223 143.8v1M87.9 180v3.8M88.4 179.6v1M122.2 166.6h2v5.1h-2z"/>
<path d="M88.4 181.4v1M88.4 183.1v1"/>
<circle cx="157.9" cy="101.8" r="2.79"/>
<circle cx="223.9" cy="101.8" r="2.79"/>
<circle cx="157.9" cy="142.5" r="2.79"/>
<circle cx="223.9" cy="142.5" r="2.79"/>
<circle cx="89.3" cy="181.9" r="2.79"/>
</g>
<g fill="none" stroke="#008484" stroke-width=".18">
<path d="M115.8 26.5h.8l-.4 .4 .3 .2v.5l-.1 .1-.6-.1M130.8 33.2v.1M131.3 32h.8l-.4 .5 .3 .1v.6l-.2 .1-.5-.1M145.7 26.5l.5 1.2 .4-1.2M161.1 39.7h-.6v1.3M173.5 34h.7M174.2 33.4v1.3M202.7 34.8h2.7M203.7 27.1h1M205.9 26.3h-.6l-.1 .6 .2-.1 .4 .1 .2 .2-.1 .4-.2 .1-.5-.1M234.7 39.7h-.6v1.3M244.6 32.5h1"/>
<path d="M84.3 43.2l.4 1.3 .4-1.3M144.2 44h-.6v1.3M34.4 69l.4 1.2 .4-1.2M83.8 78.7v1.1l.2 .2M83.8 72.4v1.1l.2 .1M84.4 79.6l.6-.1-.1-.3-.3-.1-.2 .2v.6h.5M84.4 73.2l.6-.1-.1-.2-.3-.1-.2 .2v.6h.5M102.8 78.7v1.1l.2 .2M102.8 72.4v1.1l.2 .1M103.4 79.6l.6-.1v-.3l-.4-.1-.2 .2 .1 .6h.5M103.4 73.2l.6-.1v-.2l-.4-.1-.2 .2 .1 .6h.5M180.7 75.9v.9a.41 .41 0 0 1-.5 .4"/>
<path d="M204.7 79.8h.8l-.4 .5 .3 .1v.5l-.1 .2-.6-.2M246.7 75.9v.9a.41 .41 0 0 1-.5 .4M270.8 79.8h.7l-.4 .5 .4 .1v.5l-.2 .2-.5-.2M43.4 87.2h.1a.68 .68 0 0 1 .5 .6 .68 .68 0 0 1-.5 .7 .84 .84 0 0 1-.1-1.3zM44.7 93.8h.8l-.4 .5 .3 .1v.5l-.2 .1-.5-.1M171.7 88h1M179.7 93.6l.3 1.3 .2-.9 .3 .9 .3-1.3M237.8 88h1M245.7 93.6l.3 1.3 .3-.9 .2 .9 .3-1.3M167.9 103l.5-.1 .2 .3-.8 .9h.8M180.7 116.6v.9a.41 .41 0 0 1-.5 .3M233.9 103l.5-.1 .3 .3-.8 .9h.8"/>
<path d="M246.7 116.6v.9a.41 .41 0 0 1-.5 .3M25.1 129.3l.4 1.3 .4-1.3M109.3 127.8h-.6v1.3M128.5 123h.8l-.4 .5 .3 .1v.5l-.1 .1-.6-.1M171.7 128.6h1M179.7 134.3l.3 1.2 .2-.9 .3 .9 .3-1.2M204.7 120.4h.8l-.4 .5 .3 .1v.6l-.1 .1-.6-.1M237.8 128.6h1M245.7 134.3l.3 1.2 .3-.9 .2 .9 .3-1.2M270.8 120.4h.7l-.4 .5 .4 .1v.6l-.2 .1-.5-.1M58.4 152.9l-.3-.2 .1-.2 .2-.1h.3l.1 .2v.2l-.6 .2-.1 .2v.2l.3 .3h.2l.2-.3v-.3l-.2-.2M91.1 158.5l.5 1.3 .4-1.3"/>
<path d="M124.7 159.8h.8l-.4 .5 .3 .1v.6l-.2 .1-.5-.1M167.9 143.6l.5-.1 .2 .4-.8 .9h.8M233.9 143.6l.5-.1 .3 .4-.8 .9h.8M83.9 164.3h.8M86.1 165.9l-.4 .3M98.3 170.2h.7M99.3 183l.5-.1 .3 .3-.8 .9h.8"/>
</g>
<g fill="#840000" stroke="#840000" stroke-width=".18">
<path d="M142.5 40.1h4.6v.5h-4.6z"/>
<path d="M78.2 29.5l.5 .5-1.2 .7z"/>
<path d="M78.2 23.1l.5 .5-1.2 .8z"/>
<path d="M78.2 36.2l.5 .5-1.2 .8z"/>
<path d="M78.2 49.8l.5 .5-1.2 .7z"/>
<path d="M78.2 42.5l.5 .5-1.2 .8z"/>
<path d="M88.6 181.9l1.1-.4v.7z"/>
<path d="M157.2 142.5l1-.4v.8z"/>
<path d="M157.2 101.8l1-.3v.7z"/>
<path d="M223.3 142.5l1-.4v.8z"/>
<path d="M223.3 101.8l1-.3v.7z"/>
<path d="M150.1 40.1h4.6v.5h-4.6z"/>
<path d="M223.8 40.1h4.5v.5h-4.5z"/>
<circle cx="90.2" cy="183.6" r=".25"/>
<circle cx="90.2" cy="180.1" r=".25"/>
<circle cx="158.7" cy="144.3" r=".25"/>
<circle cx="158.7" cy="140.7" r=".25"/>
<circle cx="158.7" cy="103.6" r=".25"/>
<circle cx="158.7" cy="100.1" r=".25"/>
<circle cx="224.8" cy="144.3" r=".25"/>
<circle cx="224.8" cy="140.7" r=".25"/>
<circle cx="224.8" cy="103.6" r=".25"/>
<circle cx="224.8" cy="100.1" r=".25"/>
<circle cx="108.7" cy="110.7" r=".25"/>
</g>
<path d="M112.8 38.9h3M133.1 38.9h3M162.3 40.1h3.1M105.2 132.8h3M111.5 132.8h3.1" fill="none" stroke="#840000" stroke-width=".33"/>
<path d="M118.9 129h3.5v1.6h-3.5zM93.2 168.7h1.5v3.5h-1.5zM122.4 177.5h1.6v3.6h-1.6zM78.2 181.1h3.6v1.5h-3.6z" fill="none" stroke="#840000" stroke-width=".2"/>
<g fill="none" stroke="#840000" stroke-width="1.3">
<circle cx="69.8" cy="77.7" r="1.27"/>
<circle cx="69.8" cy="71.4" r="1.27"/>
<circle cx="88.9" cy="77.7" r="1.27"/>
<circle cx="88.9" cy="71.4" r="1.27"/>
<circle cx="114.3" cy="77.7" r="1.27"/>
<circle cx="114.3" cy="71.4" r="1.27"/>
<circle cx="124.5" cy="77.7" r="1.27"/>
<circle cx="124.5" cy="71.4" r="1.27"/>
</g>
<path d="M14 14.2h48.2M259.5 39.2v1l.3 .3 .3-.1 .1-.2v-1" fill="none" stroke="#000" stroke-width=".18"/>
<g fill="none" stroke="#0000c2" stroke-width=".18">
<path d="M14 14.2v181.6h48.2v-181.6M25.6 16.8h-.3l-.2 .2 .1 .1 .4 .2v.3h-.5M64.8 14.2h39.3v43.2h-39.3zM77.8 16.8h-.3l-.2 .2 .1 .1 .4 .2v.3h-.5M107.9 16.8h172.8v36.8h-172.8zM122 19.3l-.4 1.2-.2 .1M64.8 59.9h72.4v28h-72.4zM106.7 59.9v28M79.6 63.8v1l-.2 .2h-.3M79.6 63.8h-.4l-.2 .2 .1 .5h.5M123.6 63.8v1l-.3 .2h-.3M123.6 63.8h-.4l-.2 .2 .1 .5h.5"/>
<path d="M139.7 65h143.5v96.5h-143.5zM64.8 91.7h72.4v104.1h-72.4zM74.5 94.3l-.3-.1-.2 .2 .1 .2 .4 .1v.3h-.5M87.5 94.3l-.3-.1-.2 .2v.2l.5 .1v.3h-.5"/>
</g>
<path d="M201.9 145h1.3" fill="none" stroke="#0000c2" stroke-width=".18" stroke-dasharray=".8 .8"/>
<g fill="none" stroke="#008400" stroke-width=".18">
<path d="M74.9 30.7h2.6M74.9 24.4h2.6M74.9 37.5h2.6M114.3 30.7v5.1h3.8M133.3 35.8h34.3M163.8 35.8v1.3M175.3 35.8h12.7M188 30.7h-43.2v5.1M213.4 30.7h12.7v5.1M213.4 35.8h1.2v7.6M226.1 33.3h5M238.8 25.6h26.6"/>
<path d="M246.4 33.3h3.8M74.9 51h2.6M74.9 43.8h2.6M114.3 40.9v5.1M125.7 43.4v2.6M134.6 40.9v5.1M163.8 42.2v1.2M200.7 40.9v2.5M226.1 43.4h-81.3v2.6M238.8 40.9h26.6M36.8 71.4v2.5h3.8M40.6 76.4h-13.9v1.3"/>
<path d="M43.2 98v2.6h-2.6M151.1 91.7v1.3M161.3 87.9h-2.6v8.9h14M203.2 84.1v3.8h-11.4v8.9h-11.5M217.2 91.7v1.3M227.3 87.9h-2.5v8.9h14M269.2 84.1v3.8h-11.4v8.9h-11.4M35.6 118.4h5M35.6 115.8h5M35.6 113.3h1.2M111.8 110.7h3.8v2.6M151.1 100.6v1.2"/>
<path d="M217.2 100.6v1.2M24.1 133.6v1.3h20.3M35.6 120.9h1.2v1.3M44.4 137.4h-20.3v1.3M106.7 134.9h6.3v8.9M118.1 129.8h-40.6v14h3.8M127 127.2v2.6h-3.8M151.1 132.3v1.3M161.3 128.5h-2.6v8.9h14M203.2 124.7v3.8h-11.4v8.9h-11.5M217.2 132.3v1.3M227.3 128.5h-2.5v8.9h14"/>
<path d="M269.2 124.7v3.8h-11.4v8.9h-11.4M109.2 143.8h8.9v5M151.1 141.2v1.3M217.2 141.2v1.3M86.4 167.9h7.6M86.4 173h7.6M90.2 162.8v5.1M90.2 173v3.8M121.9 174.2h1.3M123.2 164.1v1.2M123.2 173v3.8M123.2 181.9v1.2"/>
</g>
<g fill="none" stroke="#000084" stroke-width=".18">
<path d="M36.2 45.4l1.2 1.2M36.2 58.1l1.2 1.2M37.4 45.4l-1.2 1.2M37.4 58.1l-1.2 1.2M36.2 60.6l1.2 1.2M37.4 60.6l-1.2 1.2M40 78.4l1.2 1.2M41.2 78.4l-1.2 1.2M160.7 79.6l1.2 1.3M161.9 79.6l-1.2 1.3M226.7 79.6l1.2 1.3M227.9 79.6l-1.2 1.3"/>
<path d="M40 80.9l1.2 1.2M41.2 80.9l-1.2 1.2M160.7 84.7l1.2 1.2M160.7 82.2l1.2 1.2M161.9 84.7l-1.2 1.2M161.9 82.2l-1.2 1.2M191.2 84.7l1.2 1.2M192.4 84.7l-1.2 1.2M226.7 82.2l1.2 1.2M226.7 84.7l1.2 1.2M227.9 82.2l-1.2 1.2M227.9 84.7l-1.2 1.2"/>
<path d="M257.2 84.7l1.2 1.2M258.4 84.7l-1.2 1.2M160.7 120.3l1.2 1.2M160.7 122.8l1.2 1.2M160.7 125.4l1.2 1.2M161.9 120.3l-1.2 1.2M161.9 122.8l-1.2 1.2M161.9 125.4l-1.2 1.2M191.2 125.4l1.2 1.2M192.4 125.4l-1.2 1.2M226.7 120.3l1.2 1.2M226.7 125.4l1.2 1.2"/>
<path d="M226.7 122.8l1.2 1.2M227.9 120.3l-1.2 1.2M227.9 125.4l-1.2 1.2M227.9 122.8l-1.2 1.2M257.2 125.4l1.2 1.2M258.4 125.4l-1.2 1.2M80.7 140.6l1.2 1.2M81.9 140.6l-1.2 1.2M108.6 140.6l1.2 1.2M109.8 140.6l-1.2 1.2"/>
</g>
<g fill="#008400" stroke="#008400" stroke-width=".18">
<circle cx="226.1" cy="33.3" r=".46"/>
<circle cx="214.6" cy="43.4" r=".46"/>
<circle cx="224.8" cy="137.4" r=".46"/>
<circle cx="257.8" cy="128.5" r=".46"/>
<circle cx="163.8" cy="43.4" r=".46"/>
<circle cx="180.3" cy="43.4" r=".46"/>
<circle cx="200.7" cy="43.4" r=".46"/>
<circle cx="180.3" cy="35.8" r=".46"/>
<circle cx="224.8" cy="96.8" r=".46"/>
<circle cx="257.8" cy="87.9" r=".46"/>
<circle cx="191.8" cy="87.9" r=".46"/>
<circle cx="191.8" cy="128.5" r=".46"/>
<circle cx="158.7" cy="137.4" r=".46"/>
<circle cx="158.7" cy="96.8" r=".46"/>
<circle cx="152.4" cy="43.4" r=".46"/>
<circle cx="152.4" cy="35.8" r=".46"/>
<circle cx="163.8" cy="35.8" r=".46"/>
<circle cx="144.8" cy="43.4" r=".46"/>
<circle cx="144.8" cy="30.7" r=".46"/>
<circle cx="144.8" cy="35.8" r=".46"/>
<circle cx="134.6" cy="35.8" r=".46"/>
<circle cx="113" cy="143.8" r=".46"/>
<circle cx="113" cy="134.9" r=".46"/>
<circle cx="106.7" cy="129.8" r=".46"/>
<circle cx="123.2" cy="174.2" r=".46"/>
<circle cx="113" cy="129.8" r=".46"/>
<circle cx="90.2" cy="167.9" r=".46"/>
<circle cx="90.2" cy="173" r=".46"/>
<circle cx="114.3" cy="35.8" r=".46"/>
</g>
<use href="#words"/>
</svg>
